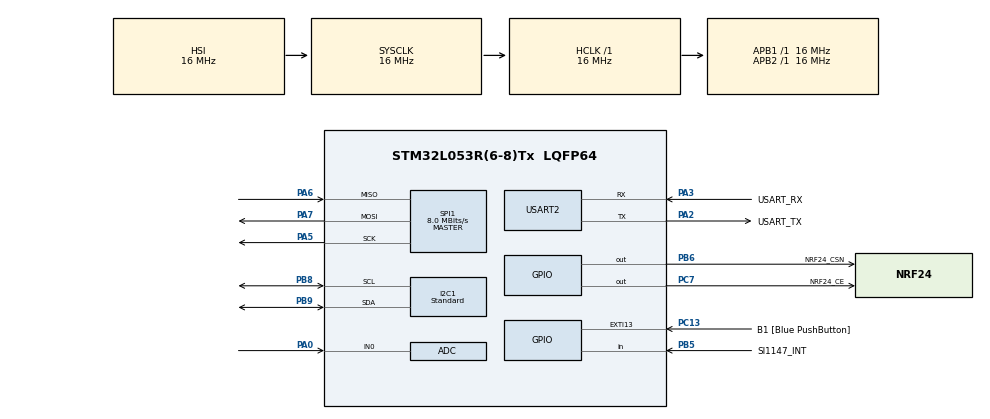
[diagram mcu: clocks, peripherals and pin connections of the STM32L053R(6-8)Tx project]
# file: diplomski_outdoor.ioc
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ADC.ClockPrescaler=ADC_CLOCK_ASYNC_DIV64
ADC.OversamplingMode=ENABLE
ADC.Ratio=ADC_OVERSAMPLING_RATIO_16
ADC.RightBitShift=ADC_RIGHTBITSHIFT_4
I2C1.I2C_Speed_Mode=I2C_Standard
I2C1.Speed=100
I2C1.Timing=0x00303D5B
Mcu.Family=STM32L0
Mcu.Name=STM32L053R(6-8)Tx
Mcu.Package=LQFP64
NVIC.EXTI4_15_IRQn=true\:0\:0\:false\:false\:true\:true\:true
NVIC.RTC_IRQn=true\:0\:0\:false\:false\:true\:true\:true
PA0.Signal=SharedAnalog_PA0
PA13.GPIO_Label=TMS
PA13.Mode=Serial_Wire
PA13.Signal=SYS_SWDIO
PA14.GPIO_Label=TCK
PA14.Mode=Serial_Wire
PA14.Signal=SYS_SWCLK
PA2.GPIO_Label=USART_TX
PA2.Mode=Asynchronous
PA2.Signal=USART2_TX
PA3.GPIO_Label=USART_RX
PA3.Mode=Asynchronous
PA3.Signal=USART2_RX
PA5.Mode=Full_Duplex_Master
PA5.Signal=SPI1_SCK
PA6.Mode=Full_Duplex_Master
PA6.Signal=SPI1_MISO
PA7.Mode=Full_Duplex_Master
PA7.Signal=SPI1_MOSI
PB5.GPIO_Label=SI1147_INT
PB5.GPIO_PuPd=GPIO_PULLUP
PB5.Signal=GPIO_Input
PB6.GPIO_Label=NRF24_CSN
PB6.Signal=GPIO_Output
PB8.GPIO_FM8=__NULL
PB8.GPIO_PuPdOD=GPIO_NOPULL
PB8.Mode=I2C
PB8.Signal=I2C1_SCL
PB9.GPIO_PuPdOD=GPIO_NOPULL
PB9.Mode=I2C
PB9.Signal=I2C1_SDA
PC13.GPIO_Label=B1 [Blue PushButton]
PC13.GPIO_ModeDefaultEXTI=GPIO_MODE_IT_FALLING
PC13.GPIO_PuPd=GPIO_PULLUP
PC13.Signal=GPXTI13
PC14-OSC32_IN.Mode=LSE-External-Oscillator
PC14-OSC32_IN.Signal=RCC_OSC32_IN
PC15-OSC32_OUT.Mode=LSE-External-Oscillator
PC15-OSC32_OUT.Signal=RCC_OSC32_OUT
PC7.GPIO_Label=NRF24_CE
PC7.Signal=GPIO_Output
PH0-OSC_IN.Signal=RCC_OSC_IN
PH1-OSC_OUT.Signal=RCC_OSC_OUT
ProjectManager.HeapSize=0x200
ProjectManager.StackSize=0x400
ProjectManager.TargetToolchain=TrueSTUDIO
RCC.AHBFreq_Value=16000000
RCC.APB1Freq_Value=16000000
RCC.APB1TimFreq_Value=16000000
RCC.APB2Freq_Value=16000000
RCC.APB2TimFreq_Value=16000000
RCC.HCLKFreq_Value=16000000
RCC.HSE_VALUE=8000000
RCC.HSI16_VALUE=16000000
RCC.HSI48_VALUE=48000000
RCC.HSI_VALUE=16000000
RCC.MSI_VALUE=2097000
RCC.RTCClockSelection=RCC_RTCCLKSOURCE_LSE
RCC.RTCClockSelectionVirtual=RCC_RTCCLKSOURCE_LSE
RCC.SYSCLKFreq_VALUE=16000000
RCC.SYSCLKSource=RCC_SYSCLKSOURCE_HSI
RCC.VCOOutputFreq_Value=48000000
RTC.Alarm-Alarm\ A=RTC_ALARM_A
SH.SharedAnalog_PA0.0=GPIO_Analog
SH.SharedAnalog_PA0.1=ADC_IN0,IN0
SPI1.CalculateBaudRate=8.0 MBits/s
SPI1.Direction=SPI_DIRECTION_2LINES
SPI1.Mode=SPI_MODE_MASTER
SPI1.VirtualType=VM_MASTER
USART2.VirtualMode-Asynchronous=VM_ASYNC
VP_RTC_VS_RTC_Activate.Mode=RTC_Enabled
VP_RTC_VS_RTC_Alarm_A_Intern.Mode=Alarm A
VP_RTC_VS_RTC_Calendar.Mode=RTC_Calendar
board=NUCLEO-L053R8

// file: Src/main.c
/* USER CODE BEGIN Header */
/**
  ******************************************************************************
  * @file           : main.c
  * @brief          : Main program body
  ******************************************************************************
  * @attention
  *
  * <h2><center>&copy; Copyright (c) 2021 STMicroelectronics.
  * All rights reserved.</center></h2>
  *
  * This software component is licensed by ST under BSD 3-Clause license,
  * the "License"; You may not use this file except in compliance with the
  * License. You may obtain a copy of the License at:
  *                        opensource.org/licenses/BSD-3-Clause
  *
  ******************************************************************************
  */
/* USER CODE END Header */

#include "main.h"

/* USER CODE BEGIN Includes */
#include <stdlib.h>
#include <stdio.h>
#include <string.h>

#include "myStructs.h"
#include "glassLCD.h"
#include "SHT21.h"
#include "rtc.h"
#include "sleep.h"
#include "BMP180.h"
#include "Si1147.h"
#include "RF24.h"
#include "communication.h"
/* USER CODE END Includes */

/* USER CODE BEGIN PD */
#define TIME_HOURS() (((__TIME__[0] - '0') * 10) + ((__TIME__[1] - '0')))
#define TIME_MINUTES() (((__TIME__[3] - '0') * 10) + ((__TIME__[4] - '0')))
#define TIME_SECONDS() (((__TIME__[6] - '0') * 10) + ((__TIME__[7] - '0')))

#define NO_DEEP_SLEEP   0
#define DEEP_SLEEP      1
#define BMP180_ERROR    1
#define SHT21_ERROR     2
#define SI1147_ERROR    3
#define AS5600_ERROR    4
#define NRF24_ERROR     5
#define RTC_ERROR       6
/* USER CODE END PD */

ADC_HandleTypeDef hadc;

I2C_HandleTypeDef hi2c1;

RTC_HandleTypeDef hrtc;

SPI_HandleTypeDef hspi1;

UART_HandleTypeDef huart2;

/* USER CODE BEGIN PV */
struct syncStructHandle syncStruct = {SYNC_HEADER, 0, 300, 1800};
const char lcdTest[] = {"88888888"};
const char errStr[] = {"ERR-%03d"};
volatile uint32_t interruptButton = 0;
/* USER CODE END PV */

void SystemClock_Config(void);
static void MX_GPIO_Init(void);
static void MX_I2C1_Init(void);
static void MX_RTC_Init(void);
static void MX_SPI1_Init(void);
static void MX_USART2_UART_Init(void);
static void MX_ADC_Init(void);
/* USER CODE BEGIN PFP */
void writeError(uint8_t _e, uint8_t _forceSleep);
/* USER CODE END PFP */

int main(void)
{

  /* MCU Configuration--------------------------------------------------------*/

  /* Reset of all peripherals, Initializes the Flash interface and the Systick. */
  HAL_Init();

  /* Configure the system clock */
  SystemClock_Config();

  /* Initialize all configured peripherals */
  MX_GPIO_Init();
  MX_I2C1_Init();
  MX_RTC_Init();
  MX_SPI1_Init();
  MX_USART2_UART_Init();
  MX_ADC_Init();
  /* USER CODE BEGIN 2 */

  // Init LCD Driver
  glassLCD_Begin();

  // Test LCD (and wait for debugger to connect)
  glassLCD_WriteData(lcdTest);
  glassLCD_SetDot(0b11111111);
  glassLCD_WriteArrow(0b11111111);
  glassLCD_Update();
  HAL_Delay(2000);

  // Init Pressure & Temp sensor
  if (!BMP180_Init()) writeError(BMP180_ERROR, DEEP_SLEEP);

  // Init Humidity & Temp sensor
  if (!SHT21_Init()) writeError(SHT21_ERROR, DEEP_SLEEP);

  // Init Si1147 Sensor for ALS and UV
  if (!Si1147_Init()) writeError(SI1147_ERROR, DEEP_SLEEP);

  RF24_init(NRF24_CE_GPIO_Port, NRF24_CE_Pin, NRF24_CSN_GPIO_Port, NRF24_CSN_Pin);
  if (!RF24_begin()) writeError(NRF24_ERROR, DEEP_SLEEP);

  // Enable UV meas.
  Si1147_SetUV();

  // Set time on RTC and alarm for wake up (FOR TEST ONLY!)
  if (RTC_SetTime(TIME_HOURS(), TIME_MINUTES(), TIME_SECONDS())) writeError(RTC_ERROR, DEEP_SLEEP);

  // Setup RF communication (speed, RF Channel, RF Power, rtc)
  communication_Setup();

  // Wait for sync signal from indoor station
  communication_Sync(&syncStruct);
  RF24_powerDown();
  /* USER CODE END 2 */

  /* Infinite loop */
  /* USER CODE BEGIN WHILE */
  uint8_t k = 0;
  while (1)
  {
	  char text[40];
	  glassLCD_Clear();
	  if (k == 0)
	  {
		  int16_t _hum = SHT21_ReadHumidity();
		  int16_t _t = SHT21_ReadTemperature();
		  sprintf(text, "%2d%01dC %2d%01d", _t / 100, abs(_t / 10 % 10), _hum / 100, abs(_hum / 10 % 10));
		  glassLCD_SetDot(0b01000010);
		  glassLCD_WriteArrow(0b10000000);
	  }
	  if (k == 1)
	  {
		  uint16_t _p = BMP180_ReadPressure();
		  sprintf(text, "%4d%1d", _p / 10, abs(_p % 10));
		  glassLCD_SetDot(0b00010000);
		  glassLCD_WriteArrow(0b01000000);
	  }
	  if (k == 2)
	  {
		  Si1147_ForceUV();
		  int16_t _uv = Si1147_GetUV();
		  int16_t _vis = Si1147_GetVis();
		  sprintf(text, "%03d %4d", _uv/10, (int)(_vis * 0.282 * 16.5));
		  glassLCD_SetDot(0b01000000);
		  glassLCD_WriteArrow(0b00100000);
	  }
	  if (k == 3)
	  {
		  // Calibrate ADC
		  HAL_ADCEx_Calibration_Start(&hadc, ADC_SINGLE_ENDED);
		  uint32_t rawAdc;
		  double voltage;
		  double current;
		  double energyJ;
		  double energy;
		  // Start ADC conversion
		  HAL_ADC_Start(&hadc);
		  // Wait for conversion to be coplete
		  HAL_ADC_PollForConversion(&hadc, 1000);
		  // Get the ADC value
		  rawAdc = HAL_ADC_GetValue(&hadc);
		  // Calculations for volage, current and energy
		  voltage = (rawAdc / 4095.0 * 3.3) - 0.0795;
		  current = voltage / (220 / 4.7);
		  energy = current / 45E-3 * 1000;
		  energyJ = (1 / 1E4) * energy * 600;
		  sprintf(text, "%2d%1d %4d", (int)(energyJ), (int)(energyJ * 10) % 10, (int)(energy));
		  glassLCD_SetDot(0b01000000);
		  glassLCD_WriteArrow(0b00010000);
	  }
	  glassLCD_WriteData(text);
	  glassLCD_Update();
	  RTC_SetAlarmEpoch(RTC_GetEpoch() + 60, RTC_ALARMMASK_DATEWEEKDAY);
	  Sleep_LightSleep();
	  if (interruptButton == GPIO_PIN_8)
	  {
	      k++;
	      k = k % 4;
	  }
    /* USER CODE END WHILE */

  }
}

void SystemClock_Config(void)
{
  RCC_OscInitTypeDef RCC_OscInitStruct = {0};
  RCC_ClkInitTypeDef RCC_ClkInitStruct = {0};
  RCC_PeriphCLKInitTypeDef PeriphClkInit = {0};

  /** Configure the main internal regulator output voltage
  */
  __HAL_PWR_VOLTAGESCALING_CONFIG(PWR_REGULATOR_VOLTAGE_SCALE1);
  /** Configure LSE Drive Capability
  */
  HAL_PWR_EnableBkUpAccess();
  __HAL_RCC_LSEDRIVE_CONFIG(RCC_LSEDRIVE_LOW);
  /** Initializes the CPU, AHB and APB busses clocks
  */
  RCC_OscInitStruct.OscillatorType = RCC_OSCILLATORTYPE_HSI|RCC_OSCILLATORTYPE_LSE;
  RCC_OscInitStruct.LSEState = RCC_LSE_ON;
  RCC_OscInitStruct.HSIState = RCC_HSI_ON;
  RCC_OscInitStruct.HSICalibrationValue = RCC_HSICALIBRATION_DEFAULT;
  RCC_OscInitStruct.PLL.PLLState = RCC_PLL_NONE;
  if (HAL_RCC_OscConfig(&RCC_OscInitStruct) != HAL_OK)
  {
    Error_Handler();
  }
  /** Initializes the CPU, AHB and APB busses clocks
  */
  RCC_ClkInitStruct.ClockType = RCC_CLOCKTYPE_HCLK|RCC_CLOCKTYPE_SYSCLK
                              |RCC_CLOCKTYPE_PCLK1|RCC_CLOCKTYPE_PCLK2;
  RCC_ClkInitStruct.SYSCLKSource = RCC_SYSCLKSOURCE_HSI;
  RCC_ClkInitStruct.AHBCLKDivider = RCC_SYSCLK_DIV1;
  RCC_ClkInitStruct.APB1CLKDivider = RCC_HCLK_DIV1;
  RCC_ClkInitStruct.APB2CLKDivider = RCC_HCLK_DIV1;

  if (HAL_RCC_ClockConfig(&RCC_ClkInitStruct, FLASH_LATENCY_0) != HAL_OK)
  {
    Error_Handler();
  }
  PeriphClkInit.PeriphClockSelection = RCC_PERIPHCLK_USART2|RCC_PERIPHCLK_I2C1
                              |RCC_PERIPHCLK_RTC;
  PeriphClkInit.Usart2ClockSelection = RCC_USART2CLKSOURCE_PCLK1;
  PeriphClkInit.I2c1ClockSelection = RCC_I2C1CLKSOURCE_PCLK1;
  PeriphClkInit.RTCClockSelection = RCC_RTCCLKSOURCE_LSE;
  if (HAL_RCCEx_PeriphCLKConfig(&PeriphClkInit) != HAL_OK)
  {
    Error_Handler();
  }
}

static void MX_ADC_Init(void)
{

  ADC_ChannelConfTypeDef sConfig = {0};

  /** Configure the global features of the ADC (Clock, Resolution, Data Alignment and number of conversion)
  */
  hadc.Instance = ADC1;
  hadc.Init.OversamplingMode = ENABLE;
  hadc.Init.Oversample.Ratio = ADC_OVERSAMPLING_RATIO_16;
  hadc.Init.Oversample.RightBitShift = ADC_RIGHTBITSHIFT_4;
  hadc.Init.Oversample.TriggeredMode = ADC_TRIGGEREDMODE_SINGLE_TRIGGER;
  hadc.Init.ClockPrescaler = ADC_CLOCK_ASYNC_DIV64;
  hadc.Init.Resolution = ADC_RESOLUTION_12B;
  hadc.Init.SamplingTime = ADC_SAMPLETIME_1CYCLE_5;
  hadc.Init.ScanConvMode = ADC_SCAN_DIRECTION_FORWARD;
  hadc.Init.DataAlign = ADC_DATAALIGN_RIGHT;
  hadc.Init.ContinuousConvMode = DISABLE;
  hadc.Init.DiscontinuousConvMode = DISABLE;
  hadc.Init.ExternalTrigConvEdge = ADC_EXTERNALTRIGCONVEDGE_NONE;
  hadc.Init.ExternalTrigConv = ADC_SOFTWARE_START;
  hadc.Init.DMAContinuousRequests = DISABLE;
  hadc.Init.EOCSelection = ADC_EOC_SINGLE_CONV;
  hadc.Init.Overrun = ADC_OVR_DATA_PRESERVED;
  hadc.Init.LowPowerAutoWait = DISABLE;
  hadc.Init.LowPowerFrequencyMode = DISABLE;
  hadc.Init.LowPowerAutoPowerOff = DISABLE;
  if (HAL_ADC_Init(&hadc) != HAL_OK)
  {
    Error_Handler();
  }
  /** Configure for the selected ADC regular channel to be converted.
  */
  sConfig.Channel = ADC_CHANNEL_0;
  sConfig.Rank = ADC_RANK_CHANNEL_NUMBER;
  if (HAL_ADC_ConfigChannel(&hadc, &sConfig) != HAL_OK)
  {
    Error_Handler();
  }

}

static void MX_I2C1_Init(void)
{

  hi2c1.Instance = I2C1;
  hi2c1.Init.Timing = 0x00303D5B;
  hi2c1.Init.OwnAddress1 = 0;
  hi2c1.Init.AddressingMode = I2C_ADDRESSINGMODE_7BIT;
  hi2c1.Init.DualAddressMode = I2C_DUALADDRESS_DISABLE;
  hi2c1.Init.OwnAddress2 = 0;
  hi2c1.Init.OwnAddress2Masks = I2C_OA2_NOMASK;
  hi2c1.Init.GeneralCallMode = I2C_GENERALCALL_DISABLE;
  hi2c1.Init.NoStretchMode = I2C_NOSTRETCH_DISABLE;
  if (HAL_I2C_Init(&hi2c1) != HAL_OK)
  {
    Error_Handler();
  }
  /** Configure Analogue filter
  */
  if (HAL_I2CEx_ConfigAnalogFilter(&hi2c1, I2C_ANALOGFILTER_ENABLE) != HAL_OK)
  {
    Error_Handler();
  }
  /** Configure Digital filter
  */
  if (HAL_I2CEx_ConfigDigitalFilter(&hi2c1, 0) != HAL_OK)
  {
    Error_Handler();
  }

}

static void MX_RTC_Init(void)
{

  RTC_TimeTypeDef sTime = {0};
  RTC_DateTypeDef sDate = {0};
  RTC_AlarmTypeDef sAlarm = {0};

  /** Initialize RTC Only
  */
  hrtc.Instance = RTC;
  hrtc.Init.HourFormat = RTC_HOURFORMAT_24;
  hrtc.Init.AsynchPrediv = 127;
  hrtc.Init.SynchPrediv = 255;
  hrtc.Init.OutPut = RTC_OUTPUT_DISABLE;
  hrtc.Init.OutPutRemap = RTC_OUTPUT_REMAP_NONE;
  hrtc.Init.OutPutPolarity = RTC_OUTPUT_POLARITY_HIGH;
  hrtc.Init.OutPutType = RTC_OUTPUT_TYPE_OPENDRAIN;
  if (HAL_RTC_Init(&hrtc) != HAL_OK)
  {
    Error_Handler();
  }

  /** Initialize RTC and set the Time and Date
  */
  sTime.Hours = 0x0;
  sTime.Minutes = 0x0;
  sTime.Seconds = 0x0;
  sTime.DayLightSaving = RTC_DAYLIGHTSAVING_NONE;
  sTime.StoreOperation = RTC_STOREOPERATION_RESET;
  if (HAL_RTC_SetTime(&hrtc, &sTime, RTC_FORMAT_BCD) != HAL_OK)
  {
    Error_Handler();
  }
  sDate.WeekDay = RTC_WEEKDAY_MONDAY;
  sDate.Month = RTC_MONTH_JANUARY;
  sDate.Date = 0x1;
  sDate.Year = 0x0;

  if (HAL_RTC_SetDate(&hrtc, &sDate, RTC_FORMAT_BCD) != HAL_OK)
  {
    Error_Handler();
  }
  /** Enable the Alarm A
  */
  sAlarm.AlarmTime.Hours = 0x0;
  sAlarm.AlarmTime.Minutes = 0x0;
  sAlarm.AlarmTime.Seconds = 0x0;
  sAlarm.AlarmTime.SubSeconds = 0x0;
  sAlarm.AlarmTime.DayLightSaving = RTC_DAYLIGHTSAVING_NONE;
  sAlarm.AlarmTime.StoreOperation = RTC_STOREOPERATION_RESET;
  sAlarm.AlarmMask = RTC_ALARMMASK_NONE;
  sAlarm.AlarmSubSecondMask = RTC_ALARMSUBSECONDMASK_ALL;
  sAlarm.AlarmDateWeekDaySel = RTC_ALARMDATEWEEKDAYSEL_DATE;
  sAlarm.AlarmDateWeekDay = 0x1;
  sAlarm.Alarm = RTC_ALARM_A;
  if (HAL_RTC_SetAlarm_IT(&hrtc, &sAlarm, RTC_FORMAT_BCD) != HAL_OK)
  {
    Error_Handler();
  }

}

static void MX_SPI1_Init(void)
{

  /* SPI1 parameter configuration*/
  hspi1.Instance = SPI1;
  hspi1.Init.Mode = SPI_MODE_MASTER;
  hspi1.Init.Direction = SPI_DIRECTION_2LINES;
  hspi1.Init.DataSize = SPI_DATASIZE_8BIT;
  hspi1.Init.CLKPolarity = SPI_POLARITY_LOW;
  hspi1.Init.CLKPhase = SPI_PHASE_1EDGE;
  hspi1.Init.NSS = SPI_NSS_SOFT;
  hspi1.Init.BaudRatePrescaler = SPI_BAUDRATEPRESCALER_2;
  hspi1.Init.FirstBit = SPI_FIRSTBIT_MSB;
  hspi1.Init.TIMode = SPI_TIMODE_DISABLE;
  hspi1.Init.CRCCalculation = SPI_CRCCALCULATION_DISABLE;
  hspi1.Init.CRCPolynomial = 7;
  if (HAL_SPI_Init(&hspi1) != HAL_OK)
  {
    Error_Handler();
  }

}

static void MX_USART2_UART_Init(void)
{

  huart2.Instance = USART2;
  huart2.Init.BaudRate = 115200;
  huart2.Init.WordLength = UART_WORDLENGTH_8B;
  huart2.Init.StopBits = UART_STOPBITS_1;
  huart2.Init.Parity = UART_PARITY_NONE;
  huart2.Init.Mode = UART_MODE_TX_RX;
  huart2.Init.HwFlowCtl = UART_HWCONTROL_NONE;
  huart2.Init.OverSampling = UART_OVERSAMPLING_16;
  huart2.Init.OneBitSampling = UART_ONE_BIT_SAMPLE_DISABLE;
  huart2.AdvancedInit.AdvFeatureInit = UART_ADVFEATURE_NO_INIT;
  if (HAL_UART_Init(&huart2) != HAL_OK)
  {
    Error_Handler();
  }

}

static void MX_GPIO_Init(void)
{
  GPIO_InitTypeDef GPIO_InitStruct = {0};

  /* GPIO Ports Clock Enable */
  __HAL_RCC_GPIOC_CLK_ENABLE();
  __HAL_RCC_GPIOH_CLK_ENABLE();
  __HAL_RCC_GPIOA_CLK_ENABLE();
  __HAL_RCC_GPIOB_CLK_ENABLE();

  /*Configure GPIO pin Output Level */
  HAL_GPIO_WritePin(NRF24_CE_GPIO_Port, NRF24_CE_Pin, GPIO_PIN_RESET);

  /*Configure GPIO pin Output Level */
  HAL_GPIO_WritePin(NRF24_CSN_GPIO_Port, NRF24_CSN_Pin, GPIO_PIN_RESET);

  /*Configure GPIO pin : PA0 */
  GPIO_InitStruct.Pin = GPIO_PIN_0;
  GPIO_InitStruct.Mode = GPIO_MODE_ANALOG;
  GPIO_InitStruct.Pull = GPIO_NOPULL;
  HAL_GPIO_Init(GPIOA, &GPIO_InitStruct);

  /*Configure GPIO pin : B3_Pin */
  GPIO_InitStruct.Pin = B3_Pin;
  GPIO_InitStruct.Mode = GPIO_MODE_IT_FALLING;
  GPIO_InitStruct.Pull = GPIO_PULLUP;
  HAL_GPIO_Init(B3_GPIO_Port, &GPIO_InitStruct);

  /*Configure GPIO pin : NRF24_CE_Pin */
  GPIO_InitStruct.Pin = NRF24_CE_Pin;
  GPIO_InitStruct.Mode = GPIO_MODE_OUTPUT_PP;
  GPIO_InitStruct.Pull = GPIO_NOPULL;
  GPIO_InitStruct.Speed = GPIO_SPEED_FREQ_LOW;
  HAL_GPIO_Init(NRF24_CE_GPIO_Port, &GPIO_InitStruct);

  /*Configure GPIO pin : B2_Pin */
  GPIO_InitStruct.Pin = B2_Pin;
  GPIO_InitStruct.Mode = GPIO_MODE_IT_FALLING;
  GPIO_InitStruct.Pull = GPIO_PULLUP;
  HAL_GPIO_Init(B2_GPIO_Port, &GPIO_InitStruct);

  /*Configure GPIO pin : SI1147_INT_Pin */
  GPIO_InitStruct.Pin = SI1147_INT_Pin;
  GPIO_InitStruct.Mode = GPIO_MODE_INPUT;
  GPIO_InitStruct.Pull = GPIO_PULLUP;
  HAL_GPIO_Init(SI1147_INT_GPIO_Port, &GPIO_InitStruct);

  /*Configure GPIO pin : NRF24_CSN_Pin */
  GPIO_InitStruct.Pin = NRF24_CSN_Pin;
  GPIO_InitStruct.Mode = GPIO_MODE_OUTPUT_PP;
  GPIO_InitStruct.Pull = GPIO_NOPULL;
  GPIO_InitStruct.Speed = GPIO_SPEED_FREQ_LOW;
  HAL_GPIO_Init(NRF24_CSN_GPIO_Port, &GPIO_InitStruct);

  /* EXTI interrupt init*/
  HAL_NVIC_SetPriority(EXTI0_1_IRQn, 0, 0);
  HAL_NVIC_EnableIRQ(EXTI0_1_IRQn);

  HAL_NVIC_SetPriority(EXTI4_15_IRQn, 0, 0);
  HAL_NVIC_EnableIRQ(EXTI4_15_IRQn);

}

/* USER CODE BEGIN 4 */
void writeError(uint8_t _e, uint8_t _forceSleep)
{
  char _c[9];
  sprintf(_c, errStr, _e);
  glassLCD_Clear();
  glassLCD_WriteData(_c);
  glassLCD_Update();
  HAL_Delay(50);
  if (_forceSleep) HAL_PWR_EnterSTANDBYMode();
}

void HAL_GPIO_EXTI_Callback(uint16_t GPIO_Pin)
{
    interruptButton = GPIO_Pin;
}

/* USER CODE END 4 */

void Error_Handler(void)
{
}

/************************ (C) COPYRIGHT STMicroelectronics *****END OF FILE****/
